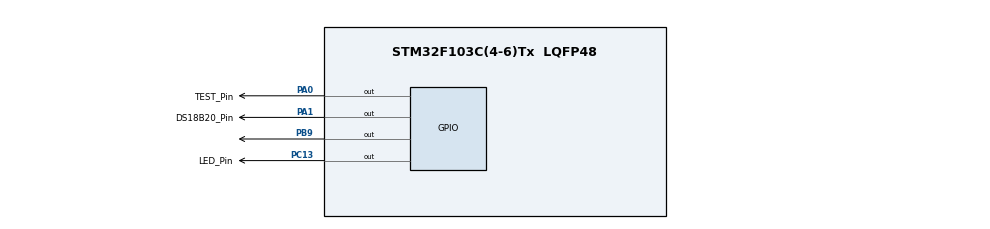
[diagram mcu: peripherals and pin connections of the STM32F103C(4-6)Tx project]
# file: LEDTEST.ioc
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Mcu.Family=STM32F1
Mcu.Name=STM32F103C(4-6)Tx
Mcu.Package=LQFP48
NVIC.PriorityGroup=NVIC_PRIORITYGROUP_4
PA0-WKUP.GPIO_Label=TEST_Pin
PA0-WKUP.Signal=GPIO_Output
PA1.GPIO_Label=DS18B20_Pin
PA1.Signal=GPIO_Output
PB9.Signal=GPIO_Output
PC13-TAMPER-RTC.GPIO_Label=LED_Pin
PC13-TAMPER-RTC.Signal=GPIO_Output
PD0-OSC_IN.Mode=HSE-External-Oscillator
PD0-OSC_IN.Signal=RCC_OSC_IN
PD1-OSC_OUT.Mode=HSE-External-Oscillator
PD1-OSC_OUT.Signal=RCC_OSC_OUT
ProjectManager.HeapSize=0x200
ProjectManager.StackSize=0x400
ProjectManager.TargetToolchain=STM32CubeIDE
RCC.APB1Freq_Value=8000000
RCC.APB2Freq_Value=8000000
TIM1.Period=65535
TIM1.Prescaler=63
VP_SYS_VS_ND.Mode=No_Debug
VP_TIM1_VS_ClockSourceINT.Mode=Internal
board=custom

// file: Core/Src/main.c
/* USER CODE BEGIN Header */
/**
  ******************************************************************************
  * @file           : main.c
  * @brief          : Main program body
  ******************************************************************************
  * @attention
  *
  * Copyright (c) 2024 STMicroelectronics.
  * All rights reserved.
  *
  * This software is licensed under terms that can be found in the LICENSE file
  * in the root directory of this software component.
  * If no LICENSE file comes with this software, it is provided AS-IS.
  *
  ******************************************************************************
  */
/* USER CODE END Header */
#include "main.h"
#include"gpio.h"
#include"tim.h"
#include "stm32f1xx_hal.h"
/* USER CODE BEGIN Includes */
#include "onewire_SONDE.h"
#include "ds18b20_PFE.h"
#include "string.h"
//#define FIREBASE_HOST "temp-f147e-default-rtdb.firebaseio.com"
//#define FIREBASE_AUTH "VyblhC0AozCIQdBIwnN4i6FaaCqRizLhaREYGM7k"
/* USER CODE END Includes */

/* USER CODE BEGIN PD */
//float Temperature;
//char message[64];
//char string[64];
	//uint8_t ROM_tmp[8];

/* USER CODE END PD */

/* USER CODE BEGIN PV */

float Temperature;
char message[64];
//char string[64];

/* USER CODE END PV */

void SystemClock_Config(void);

/* USER CODE BEGIN 0 */
//float Temperature;
//char string[64];
/* USER CODE END 0 */

int main(void)
{

  /* MCU Configuration--------------------------------------------------------*/

  /* Reset of all peripherals, Initializes the Flash interface and the Systick. */
  HAL_Init();

  /* Configure the system clock */
  SystemClock_Config();

  /* Initialize all configured peripherals */
  MX_GPIO_Init();
  MX_TIM1_Init();
  /* USER CODE BEGIN 2 */
  DS18B20_Init(DS18B20_Resolution_12bits);
  HAL_GPIO_WritePin(TEST_GPIO_Port, TEST_Pin, 0);
	uint8_t ROM_tmp[8];
	   		uint8_t i;
  /* USER CODE END 2 */

  /* Infinite loop */
  while (1)
  {

    /* USER CODE BEGIN 3 */
	  DS18B20_ReadAll();
	  HAL_GPIO_WritePin(TEST_GPIO_Port, TEST_Pin, 1);
	       DS18B20_StartAll();
	       HAL_GPIO_WritePin(TEST_GPIO_Port, TEST_Pin, 0);

	 	for(i = 0; i < DS18B20_Quantity(); i++)
	 		{
	 			if(DS18B20_GetTemperature(i, &Temperature))
	 			{
	 				DS18B20_GetROM(i, ROM_tmp);
	 				memset(message, 0, sizeof(message));
	 				sprintf(message, "%.2f C", Temperature);

	 				 if (Temperature > 30.0f) // Ajuster le seuil de température selon vos besoins
	 					 {
	 				 HAL_GPIO_WritePin(GPIOB, GPIO_PIN_9, GPIO_PIN_RESET); // Activer le relais pour allumer le ventilateur

	 					 }
	 				else
	 			         {
	 			   HAL_GPIO_WritePin(GPIOB, GPIO_PIN_9, GPIO_PIN_SET); // Désactiver le relais pour éteindre le ventilateur

	 			         }
	 			}
	 		}

	 	HAL_Delay(1000);
	 			HAL_GPIO_TogglePin(LED_GPIO_Port, LED_Pin);
  }
  /* USER CODE END 3 */
}

void SystemClock_Config(void)
{
  RCC_OscInitTypeDef RCC_OscInitStruct = {0};
  RCC_ClkInitTypeDef RCC_ClkInitStruct = {0};

  /** Initializes the RCC Oscillators according to the specified parameters
  * in the RCC_OscInitTypeDef structure.
  */
  RCC_OscInitStruct.OscillatorType = RCC_OSCILLATORTYPE_HSE;
  RCC_OscInitStruct.HSEState = RCC_HSE_ON;
  RCC_OscInitStruct.HSEPredivValue = RCC_HSE_PREDIV_DIV1;
  RCC_OscInitStruct.HSIState = RCC_HSI_ON;
  RCC_OscInitStruct.PLL.PLLState = RCC_PLL_ON;
  RCC_OscInitStruct.PLL.PLLSource = RCC_PLLSOURCE_HSE;
  RCC_OscInitStruct.PLL.PLLMUL = RCC_PLL_MUL6;
  if (HAL_RCC_OscConfig(&RCC_OscInitStruct) != HAL_OK)
  {
	  _Error_Handler(__FILE__, __LINE__);
  }
  /** Initializes the CPU, AHB and APB buses clocks
  */
  RCC_ClkInitStruct.ClockType = RCC_CLOCKTYPE_HCLK|RCC_CLOCKTYPE_SYSCLK
                              |RCC_CLOCKTYPE_PCLK1|RCC_CLOCKTYPE_PCLK2;
  RCC_ClkInitStruct.SYSCLKSource = RCC_SYSCLKSOURCE_PLLCLK;
  RCC_ClkInitStruct.AHBCLKDivider = RCC_SYSCLK_DIV1;
  RCC_ClkInitStruct.APB1CLKDivider = RCC_HCLK_DIV2;
  RCC_ClkInitStruct.APB2CLKDivider = RCC_HCLK_DIV1;

  if (HAL_RCC_ClockConfig(&RCC_ClkInitStruct, FLASH_LATENCY_1) != HAL_OK)
  {
	  _Error_Handler(__FILE__, __LINE__);
  }

}

void _Error_Handler(char * file, int line)
{
  while(1)
  {
  }
}
